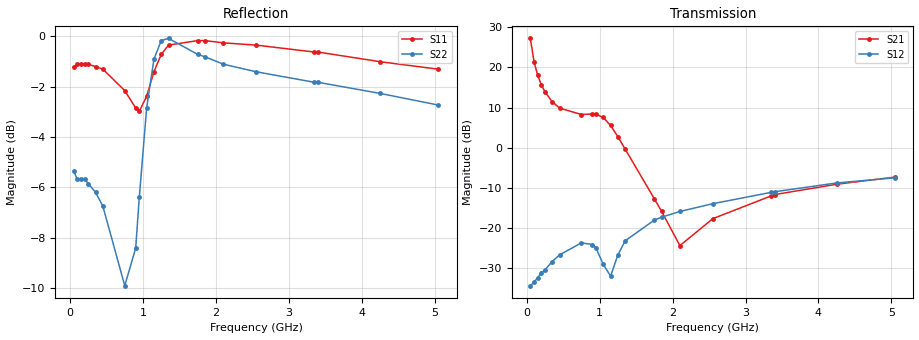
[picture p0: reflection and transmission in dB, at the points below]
!AT-33225
!S-PARAMETERS at Vce=6.0V  Ic=150mA.  LAST UPDATED 08-05-96
# ghz s ma r 50
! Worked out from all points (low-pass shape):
!   101 points, 50 MHz to 5.05 GHz, reference 50 ohm
!   highest |S21| = 27.26 dB at 50 MHz (marker M1); lowest = -24.4 dB at 2.1 GHz (marker M2)
!   |S21| within 3 dB of the highest: start of sweep to 75.95 MHz
!   lowest |S11| = -3.0 dB at 950 MHz (marker M3), VSWR 5.90, Z = 8.5 + j2.54 ohm
!   |S11| at or under -10 dB: nowhere
!   |S22| runs from -10.2 to -0.1 dB; largest |S21 - S12| = 23
!   S11 on the Smith chart (normalised r, x): 50 MHz: 0.07, -0.17; 450 MHz: 0.08, +0.05; 1.85 GHz: 0.01, +0.17; 3.35 GHz: 0.04, +0.36; 5.05 GHz: 0.10, +0.60
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0.05  0.87 -161.0  23.07 100.0  0.019 25.0  0.54 -149.0
0.1  0.88 -172.0  11.86 91.0  0.021 30.0  0.52 -166.0
0.15  0.88 -176.0  8 86.0  0.024 36.0  0.52 -172.0
0.2  0.88 -179.0  6.1 82.0  0.027 40.0  0.52 -176.0
0.25  0.88 179.0  4.97 78.0  0.03 44.0  0.51 -178.0
0.35  0.87 176.0  3.74 72.0  0.038 48.0  0.49 179.0
0.45  0.86 174.0  3.12 65.0  0.046 49.0  0.46 178.0
0.75  0.78 169.0  2.59 37.0  0.065 39.0  0.32 -169.0
0.9  0.72 172.0  2.63 13.0  0.062 26.0  0.38 -137.0
0.95  0.71 174.0  2.61 3.0  0.056 21.0  0.48 -131.0
1.05  0.76 180.0  2.38 -22.0  0.035 20.0  0.72 -135.0
1.15  0.85 -180.0  1.89 -46.0  0.025 69.0  0.9 -148.0
1.25  0.92 177.0  1.37 -65.0  0.046 94.0  0.98 -160.0
1.35  0.96 174.0  0.96 -80.0  0.069 92.0  0.99 -169.0
1.75  0.98 163.0  0.23 -119.0  0.125 78.0  0.92 171.0
1.85  0.98 161.0  0.16 -130.0  0.136 76.0  0.91 168.0
2.1  0.97 157.0  0.06 168.0  0.16 70.0  0.88 162.0
2.55  0.96 151.0  0.13 81.0  0.2 62.0  0.85 153.0
3.35  0.93 140.0  0.25 54.0  0.277 50.0  0.81 138.0
3.4  0.93 140.0  0.26 53.0  0.282 49.0  0.81 137.0
4.25  0.89 128.0  0.35 35.0  0.363 32.0  0.77 117.0
5.05  0.86 118.0  0.43 18.0  0.421 18.0  0.73 95.0
